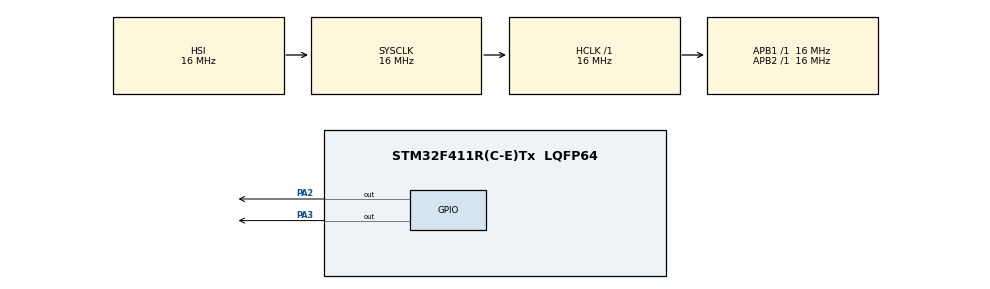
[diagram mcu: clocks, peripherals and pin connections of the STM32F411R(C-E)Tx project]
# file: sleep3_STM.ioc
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Mcu.Family=STM32F4
Mcu.Name=STM32F411R(C-E)Tx
Mcu.Package=LQFP64
NVIC.PriorityGroup=NVIC_PRIORITYGROUP_4
NVIC.TIM5_IRQn=true\:15\:0\:false\:false\:true\:false\:true\:true
NVIC.TimeBase=TIM5_IRQn
NVIC.TimeBaseIP=TIM5
PA2.Signal=GPIO_Output
PA3.Signal=GPIO_Output
ProjectManager.HeapSize=0x200
ProjectManager.StackSize=0x400
ProjectManager.TargetToolchain=STM32CubeIDE
RCC.AHBFreq_Value=16000000
RCC.APB1Freq_Value=16000000
RCC.APB2Freq_Value=16000000
RCC.CortexFreq_Value=16000000
RCC.HSE_VALUE=25000000
RCC.HSI_VALUE=16000000
RCC.LSE_VALUE=32768
RCC.SYSCLKFreq_VALUE=16000000
RCC.VCOOutputFreq_Value=192000000
VP_SYS_VS_tim5.Mode=TIM5
board=custom

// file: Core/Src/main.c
/* USER CODE BEGIN Header */
/**
  ******************************************************************************
  * @file           : main.c
  * @brief          : Main program body
  ******************************************************************************
  * @attention
  *
  * Copyright (c) 2026 STMicroelectronics.
  * All rights reserved.
  *
  * This software is licensed under terms that can be found in the LICENSE file
  * in the root directory of this software component.
  * If no LICENSE file comes with this software, it is provided AS-IS.
  *
  ******************************************************************************
  */
/* USER CODE END Header */
#include "main.h"

/* USER CODE BEGIN Includes */
#include "FreeRTOS.h"
#include "task.h"
/* USER CODE END Includes */

void SystemClock_Config(void);
static void MX_GPIO_Init(void);

/* USER CODE BEGIN 0 */
static void LedPA2_Task(void *argument);
static void LedPA3_Task(void *argument);

static void LedPA2_Task(void *argument)
{
	for (;;)
	  {
	    HAL_GPIO_TogglePin(GPIOA, GPIO_PIN_2);
	    vTaskDelay(pdMS_TO_TICKS(200));
	  }
}

static void LedPA3_Task(void *argument)
{
	for (;;)
	  {
	    HAL_GPIO_TogglePin(GPIOA, GPIO_PIN_3);
	    vTaskDelay(pdMS_TO_TICKS(200));
	  }
}

/* USER CODE END 0 */

int main(void)
{

  /* MCU Configuration--------------------------------------------------------*/

  /* Reset of all peripherals, Initializes the Flash interface and the Systick. */
  HAL_Init();

  /* Configure the system clock */
  SystemClock_Config();

  /* Initialize all configured peripherals */
  MX_GPIO_Init();
  /* USER CODE BEGIN 2 */
  xTaskCreate(LedPA2_Task, "PA2", 256, NULL, 2, NULL);
  xTaskCreate(LedPA3_Task, "PA3", 256, NULL, 1, NULL);

  //HAL_GPIO_TogglePin(GPIOA, GPIO_PIN_2);
  //HAL_GPIO_TogglePin(GPIOA, GPIO_PIN_3);

  NVIC_SetPriority(PendSV_IRQn, 15);
  NVIC_SetPriority(SysTick_IRQn, 15);

  vTaskStartScheduler();
  /* USER CODE END 2 */

  /* Infinite loop */
  while (1)
  {

  }
}

void SystemClock_Config(void)
{
  RCC_OscInitTypeDef RCC_OscInitStruct = {0};
  RCC_ClkInitTypeDef RCC_ClkInitStruct = {0};

  /** Configure the main internal regulator output voltage
  */
  __HAL_RCC_PWR_CLK_ENABLE();
  __HAL_PWR_VOLTAGESCALING_CONFIG(PWR_REGULATOR_VOLTAGE_SCALE1);

  /** Initializes the RCC Oscillators according to the specified parameters
  * in the RCC_OscInitTypeDef structure.
  */
  RCC_OscInitStruct.OscillatorType = RCC_OSCILLATORTYPE_HSI;
  RCC_OscInitStruct.HSIState = RCC_HSI_ON;
  RCC_OscInitStruct.HSICalibrationValue = RCC_HSICALIBRATION_DEFAULT;
  RCC_OscInitStruct.PLL.PLLState = RCC_PLL_NONE;
  if (HAL_RCC_OscConfig(&RCC_OscInitStruct) != HAL_OK)
  {
    Error_Handler();
  }

  /** Initializes the CPU, AHB and APB buses clocks
  */
  RCC_ClkInitStruct.ClockType = RCC_CLOCKTYPE_HCLK|RCC_CLOCKTYPE_SYSCLK
                              |RCC_CLOCKTYPE_PCLK1|RCC_CLOCKTYPE_PCLK2;
  RCC_ClkInitStruct.SYSCLKSource = RCC_SYSCLKSOURCE_HSI;
  RCC_ClkInitStruct.AHBCLKDivider = RCC_SYSCLK_DIV1;
  RCC_ClkInitStruct.APB1CLKDivider = RCC_HCLK_DIV1;
  RCC_ClkInitStruct.APB2CLKDivider = RCC_HCLK_DIV1;

  if (HAL_RCC_ClockConfig(&RCC_ClkInitStruct, FLASH_LATENCY_0) != HAL_OK)
  {
    Error_Handler();
  }
}

static void MX_GPIO_Init(void)
{
  GPIO_InitTypeDef GPIO_InitStruct = {0};

  /* GPIO Ports Clock Enable */
  __HAL_RCC_GPIOH_CLK_ENABLE();
  __HAL_RCC_GPIOD_CLK_ENABLE();

  /*Configure GPIO pin Output Level */
  HAL_GPIO_WritePin(GPIOD, GPIO_PIN_13|GPIO_PIN_14, GPIO_PIN_RESET);

  /*Configure GPIO pins : PD13 PD14 */
  GPIO_InitStruct.Pin = GPIO_PIN_13|GPIO_PIN_14;
  GPIO_InitStruct.Mode = GPIO_MODE_OUTPUT_PP;
  GPIO_InitStruct.Pull = GPIO_NOPULL;
  GPIO_InitStruct.Speed = GPIO_SPEED_FREQ_LOW;
  HAL_GPIO_Init(GPIOD, &GPIO_InitStruct);

}

void HAL_TIM_PeriodElapsedCallback(TIM_HandleTypeDef *htim)
{
  if (htim->Instance == TIM4)
  {
    HAL_IncTick();
  }
}

void Error_Handler(void)
{
  __disable_irq();
  while (1)
  {
  }
}
